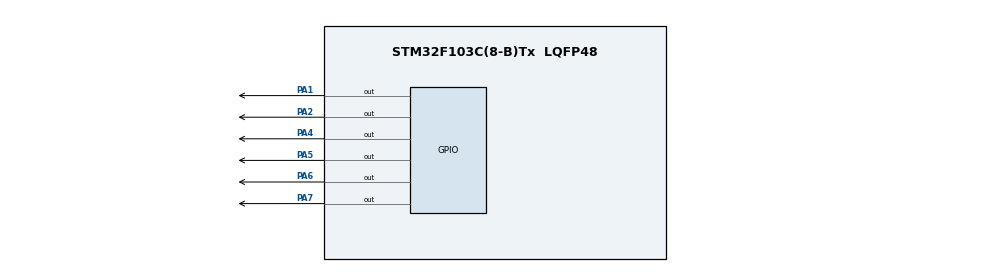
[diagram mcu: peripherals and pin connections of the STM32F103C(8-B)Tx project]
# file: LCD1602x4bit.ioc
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Mcu.Family=STM32F1
RCC.PLLSourceVirtual=RCC_PLLSOURCE_HSE
PD1-OSC_OUT.Mode=HSE-External-Oscillator
PD0-OSC_IN.Signal=RCC_OSC_IN
RCC.APB1CLKDivider=RCC_HCLK_DIV2
RCC.SYSCLKSource=RCC_SYSCLKSOURCE_PLLCLK
ProjectManager.StackSize=0x400
PD1-OSC_OUT.Signal=RCC_OSC_OUT
PA13.Signal=SYS_JTMS-SWDIO
ProjectManager.TargetToolchain=MDK-ARM V5
RCC.HCLKFreq_Value=64000000
RCC.APB2TimFreq_Value=64000000
RCC.USBFreq_Value=64000000
PA1.Signal=GPIO_Output
RCC.AHBFreq_Value=64000000
PD0-OSC_IN.Mode=HSE-External-Oscillator
PA5.Signal=GPIO_Output
board=custom
RCC.PLLMUL=RCC_PLL_MUL8
RCC.APB2Freq_Value=32000000
PA14.Mode=Serial_Wire
PA13.Mode=Serial_Wire
Mcu.Name=STM32F103C(8-B)Tx
PA2.Signal=GPIO_Output
PA4.Signal=GPIO_Output
RCC.SYSCLKFreq_VALUE=64000000
Mcu.Package=LQFP48
PA6.Signal=GPIO_Output
PA14.Signal=SYS_JTCK-SWCLK
ProjectManager.HeapSize=0x200
NVIC.PriorityGroup=NVIC_PRIORITYGROUP_4
RCC.APB2CLKDivider=RCC_HCLK_DIV2
RCC.APB1TimFreq_Value=64000000
RCC.APB1Freq_Value=32000000
PA7.Signal=GPIO_Output

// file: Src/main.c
#include "main.h"
#include "LCD1602x4bit.h"

void SystemClock_Config(void);
static void MX_GPIO_Init(void);

int main(void)
{

  HAL_Init();
  SystemClock_Config();
  MX_GPIO_Init();

	lcd_init(PB1,PB2,PB4,PB5,PB6,PB7);  // RS,EN,D4,D5,D6,D7   RW connect to GND
	lcd_goto_XY(1,4);
	lcd_send_string("LCD 1602");
	lcd_goto_XY(2,0);
	lcd_send_string("4-Bit Interface");
  while (1)
  {

  }
}

void SystemClock_Config(void)
{
  RCC_OscInitTypeDef RCC_OscInitStruct = {0};
  RCC_ClkInitTypeDef RCC_ClkInitStruct = {0};
  RCC_OscInitStruct.OscillatorType = RCC_OSCILLATORTYPE_HSE;
  RCC_OscInitStruct.HSEState = RCC_HSE_ON;
  RCC_OscInitStruct.HSEPredivValue = RCC_HSE_PREDIV_DIV1;
  RCC_OscInitStruct.HSIState = RCC_HSI_ON;
  RCC_OscInitStruct.PLL.PLLState = RCC_PLL_ON;
  RCC_OscInitStruct.PLL.PLLSource = RCC_PLLSOURCE_HSE;
  RCC_OscInitStruct.PLL.PLLMUL = RCC_PLL_MUL9;
  if (HAL_RCC_OscConfig(&RCC_OscInitStruct) != HAL_OK)
  {
    Error_Handler();
  }
  RCC_ClkInitStruct.ClockType = RCC_CLOCKTYPE_HCLK|RCC_CLOCKTYPE_SYSCLK
                              |RCC_CLOCKTYPE_PCLK1|RCC_CLOCKTYPE_PCLK2;
  RCC_ClkInitStruct.SYSCLKSource = RCC_SYSCLKSOURCE_PLLCLK;
  RCC_ClkInitStruct.AHBCLKDivider = RCC_SYSCLK_DIV1;
  RCC_ClkInitStruct.APB1CLKDivider = RCC_HCLK_DIV2;
  RCC_ClkInitStruct.APB2CLKDivider = RCC_HCLK_DIV2;

  if (HAL_RCC_ClockConfig(&RCC_ClkInitStruct, FLASH_LATENCY_2) != HAL_OK)
  {
    Error_Handler();
  }
}

static void MX_GPIO_Init(void)
{
  GPIO_InitTypeDef GPIO_InitStruct = {0};

  /* GPIO Ports Clock Enable */
  __HAL_RCC_GPIOD_CLK_ENABLE();
  __HAL_RCC_GPIOA_CLK_ENABLE();
	__HAL_RCC_GPIOB_CLK_ENABLE();
	__HAL_RCC_GPIOC_CLK_ENABLE();

  /*Configure GPIO pin Output Level */
  HAL_GPIO_WritePin(GPIOC, GPIO_PIN_13, GPIO_PIN_RESET);

  /*Configure GPIO pins : PA1 PA2 PA4 PA5
                           PA6 PA7 */
  GPIO_InitStruct.Pin = GPIO_PIN_13;
  GPIO_InitStruct.Mode = GPIO_MODE_OUTPUT_PP;
  GPIO_InitStruct.Pull = GPIO_NOPULL;
  GPIO_InitStruct.Speed = GPIO_SPEED_FREQ_LOW;
  HAL_GPIO_Init(GPIOC, &GPIO_InitStruct);

}

void Error_Handler(void)
{

}

/************************ (C) COPYRIGHT STMicroelectronics *****END OF FILE****/
